VERSION 5.7 ;
  NOWIREEXTENSIONATPIN ON ;
  DIVIDERCHAR "/" ;
  BUSBITCHARS "[]" ;
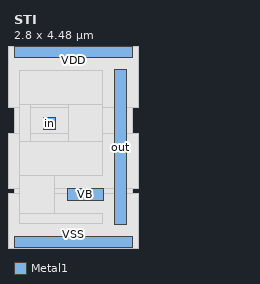
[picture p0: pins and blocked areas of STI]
MACRO STI
  CLASS core ;
  FOREIGN STI ;
  ORIGIN 0.000 0.000 ;
  SIZE 2.800 BY 4.480 ;
  SITE site056um ;
  PIN VDD
    DIRECTION INOUT ;
    USE POWER ;
    PORT
      LAYER Metal1 ;
        RECT 0.000 4.340 2.800 4.620 ;
    END
  END VDD
  PIN VSS
    DIRECTION INOUT ;
    USE GROUND ;
    PORT
      LAYER Metal1 ;
        RECT 0.000 -0.140 2.800 0.140 ;
    END
  END VSS
  PIN out
    DIRECTION OUTPUT ;
    USE SIGNAL ;
    ANTENNAGATEAREA 0.246400 ;
    ANTENNADIFFAREA 0.522800 ;
    PORT
      LAYER Metal1 ;
        RECT 2.380 0.420 2.660 4.060 ;
    END
  END out
  PIN in
    DIRECTION INPUT ;
    USE SIGNAL ;
    ANTENNAGATEAREA 0.453200 ;
    PORT
      LAYER Metal1 ;
        RECT 0.700 2.660 0.980 2.940 ;
    END
  END in
  PIN VB
    DIRECTION INPUT ;
    USE SIGNAL ;
    ANTENNAGATEAREA 0.246400 ;
    PORT
      LAYER Metal1 ;
        RECT 1.260 0.980 2.100 1.260 ;
    END
  END VB
  OBS
      LAYER Nwell ;
        RECT -0.455 3.160 3.325 4.755 ;
        RECT 0.000 2.560 2.800 3.160 ;
        RECT -0.455 1.260 3.130 2.560 ;
        RECT 0.000 1.135 2.800 1.260 ;
      LAYER Pwell ;
        RECT -0.455 -0.190 3.080 1.135 ;
      LAYER Metal1 ;
        RECT 0.135 3.240 2.080 4.040 ;
        RECT 0.135 2.360 0.400 3.240 ;
        RECT 1.280 2.360 2.080 3.240 ;
        RECT 0.135 1.560 2.080 2.360 ;
        RECT 0.135 0.680 0.960 1.560 ;
        RECT 0.135 0.440 2.080 0.680 ;
  END
END STI
END LIBRARY

